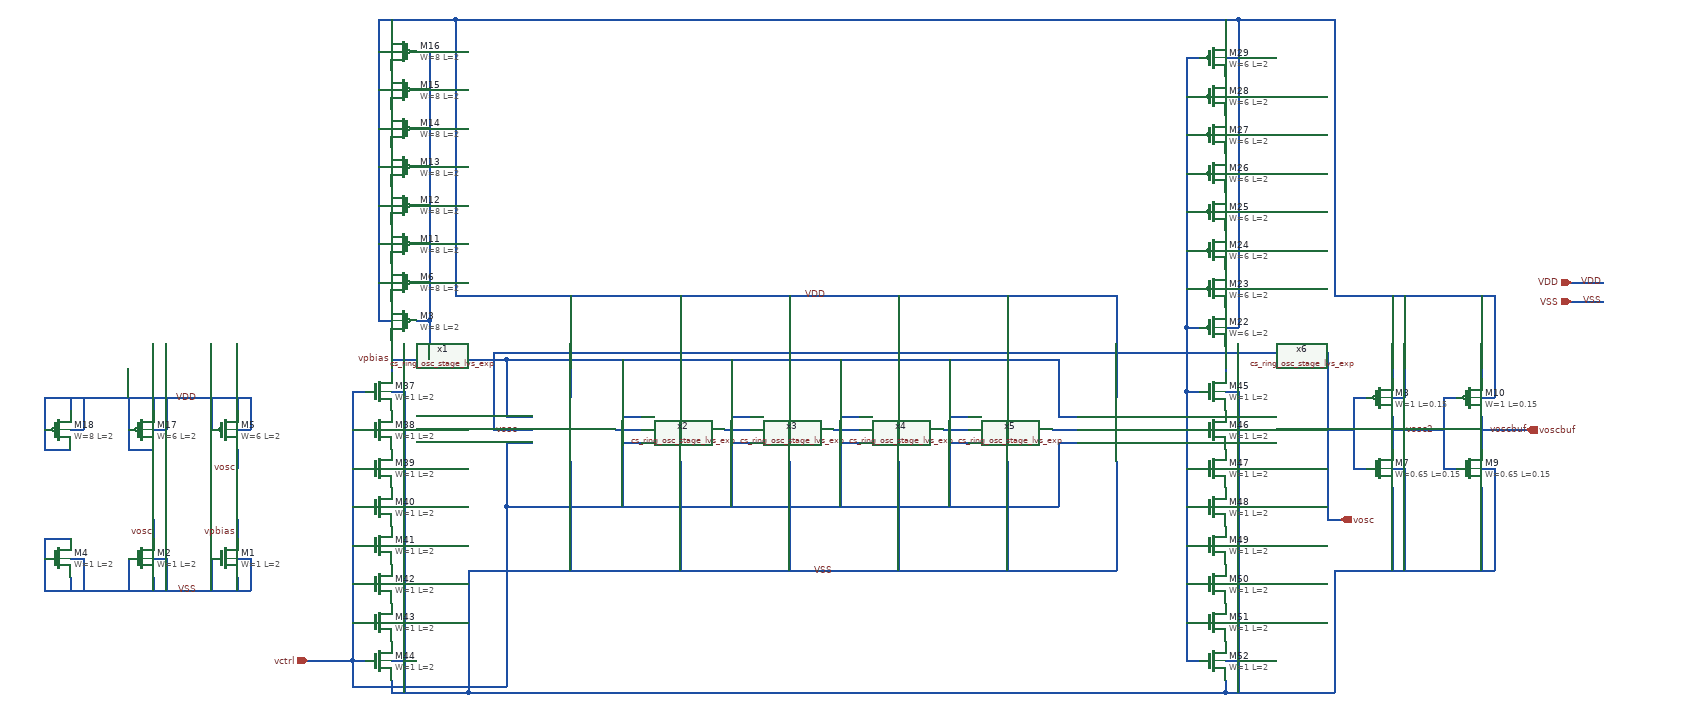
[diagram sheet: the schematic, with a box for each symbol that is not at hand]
v {xschem version=2.9.9 file_version=1.2 

* Copyright 2020 Stefan Frederik Schippers
* 
* Licensed under the Apache License, Version 2.0 (the "License");
* you may not use this file except in compliance with the License.
* You may obtain a copy of the License at
*
*     https://www.apache.org/licenses/LICENSE-2.0
*
* Unless required by applicable law or agreed to in writing, software
* distributed under the License is distributed on an "AS IS" BASIS,
* WITHOUT WARRANTIES OR CONDITIONS OF ANY KIND, either express or implied.
* See the License for the specific language governing permissions and
* limitations under the License.

}
G {}
K {}
V {}
S {}
E {}
N -120 -140 -50 -140 { lab=vctrl}
N 130 -610 190 -610 { lab=vpbias}
N 190 -610 190 -520 { lab=vpbias}
N 190 -520 230 -520 { lab=vpbias}
N 190 -480 190 -380 { lab=vctrl}
N 190 -480 230 -480 { lab=vctrl}
N 360 -500 400 -500 { lab=#net1}
N 530 -500 570 -500 { lab=#net2}
N 700 -500 740 -500 { lab=#net3}
N 870 -500 910 -500 { lab=#net4}
N 1040 -500 1080 -500 { lab=#net5}
N 1210 -500 1250 -500 { lab=#net6}
N 190 -610 1050 -610 { lab=vpbias}
N 1050 -520 1080 -520 { lab=vpbias}
N 190 -380 1050 -380 { lab=vctrl}
N 1050 -480 1080 -480 { lab=vctrl}
N 880 -520 910 -520 { lab=vpbias}
N 880 -480 910 -480 { lab=vctrl}
N 710 -520 740 -520 { lab=vpbias}
N 710 -480 740 -480 { lab=vctrl}
N 540 -480 570 -480 { lab=vctrl}
N 540 -520 570 -520 { lab=vpbias}
N 370 -520 400 -520 { lab=vpbias}
N 370 -610 370 -520 { lab=vpbias}
N 370 -480 400 -480 { lab=vctrl}
N 370 -480 370 -380 { lab=vctrl}
N 170 -500 230 -500 { lab=vosc}
N 1470 -500 1470 -360 { lab=vosc}
N 1570 -550 1590 -550 { lab=VDD}
N 1570 -520 1570 -470 { lab=vosc2}
N 1570 -440 1590 -440 { lab=VSS}
N 1510 -550 1510 -490 { lab=vosc}
N 1510 -550 1530 -550 { lab=vosc}
N 1510 -490 1510 -440 { lab=vosc}
N 1510 -440 1530 -440 { lab=vosc}
N 1570 -710 1570 -580 { lab=VDD}
N 1590 -710 1590 -550 { lab=VDD}
N 1570 -410 1570 -280 { lab=VSS}
N 1590 -440 1590 -280 { lab=VSS}
N 1710 -550 1730 -550 { lab=VDD}
N 1710 -520 1710 -470 { lab=voscbuf}
N 1710 -440 1730 -440 { lab=VSS}
N 1650 -550 1650 -490 { lab=vosc2}
N 1650 -550 1670 -550 { lab=vosc2}
N 1650 -490 1650 -440 { lab=vosc2}
N 1650 -440 1670 -440 { lab=vosc2}
N 1710 -710 1710 -580 { lab=VDD}
N 1730 -710 1730 -550 { lab=VDD}
N 1710 -410 1710 -280 { lab=VSS}
N 1730 -440 1730 -280 { lab=VSS}
N 1570 -500 1650 -500 { lab=vosc2}
N 1470 -500 1510 -500 { lab=vosc}
N 290 -710 290 -550 { lab=VDD}
N 290 -450 290 -280 { lab=VSS}
N 540 -610 540 -520 { lab=vpbias}
N 540 -480 540 -380 { lab=vctrl}
N 460 -710 460 -550 { lab=VDD}
N 460 -450 460 -280 { lab=VSS}
N 710 -610 710 -520 { lab=vpbias}
N 710 -480 710 -380 { lab=vctrl}
N 630 -710 630 -550 { lab=VDD}
N 630 -450 630 -280 { lab=VSS}
N 880 -610 880 -520 { lab=vpbias}
N 880 -480 880 -380 { lab=vctrl}
N 800 -710 800 -550 { lab=VDD}
N 800 -450 800 -280 { lab=VSS}
N 1050 -610 1050 -520 { lab=vpbias}
N 1050 -480 1050 -380 { lab=vctrl}
N 970 -710 970 -550 { lab=VDD}
N 970 -450 970 -280 { lab=VSS}
N 1140 -710 1140 -550 { lab=VDD}
N 1140 -450 1140 -280 { lab=VSS}
N 1850 -730 1900 -730 { lab=VDD}
N 1850 -700 1900 -700 { lab=VSS}
N 1710 -500 1780 -500 { lab=voscbuf}
N 1470 -360 1490 -360 { lab=vosc}
N -10 -670 10 -670 { lab=VDD}
N 10 -1140 10 -1120 { lab=VDD}
N -10 -730 10 -730 { lab=VDD}
N -10 -790 10 -790 { lab=VDD}
N -10 -850 10 -850 { lab=VDD}
N -10 -910 10 -910 { lab=VDD}
N -10 -970 10 -970 { lab=VDD}
N -10 -1030 10 -1030 { lab=VDD}
N -10 -1090 10 -1090 { lab=VDD}
N 50 -1090 70 -1090 { lab=vpbias}
N 70 -1090 70 -670 { lab=vpbias}
N 50 -670 70 -670 { lab=vpbias}
N 50 -730 70 -730 { lab=vpbias}
N 50 -790 70 -790 { lab=vpbias}
N 50 -850 70 -850 { lab=vpbias}
N 50 -910 70 -910 { lab=vpbias}
N 50 -970 70 -970 { lab=vpbias}
N 50 -1030 70 -1030 { lab=vpbias}
N 10 -110 10 -90 { lab=VSS}
N 10 -560 30 -560 { lab=VSS}
N 10 -500 30 -500 { lab=VSS}
N 10 -440 30 -440 { lab=VSS}
N 10 -380 30 -380 { lab=VSS}
N 10 -320 30 -320 { lab=VSS}
N 10 -260 30 -260 { lab=VSS}
N 10 -200 30 -200 { lab=VSS}
N 10 -140 30 -140 { lab=VSS}
N -50 -560 -30 -560 { lab=vctrl}
N -50 -560 -50 -140 { lab=vctrl}
N -50 -140 -30 -140 { lab=vctrl}
N -50 -200 -30 -200 { lab=vctrl}
N -50 -260 -30 -260 { lab=vctrl}
N -50 -320 -30 -320 { lab=vctrl}
N -50 -380 -30 -380 { lab=vctrl}
N -50 -440 -30 -440 { lab=vctrl}
N -50 -500 -30 -500 { lab=vctrl}
N 30 -560 30 -90 { lab=VSS}
N 10 -640 10 -590 { lab=vpbias}
N 10 -90 130 -90 { lab=VSS}
N 130 -280 130 -90 { lab=VSS}
N 190 -380 190 -100 { lab=vctrl}
N -50 -100 190 -100 { lab=vctrl}
N -50 -140 -50 -100 { lab=vctrl}
N 10 -610 130 -610 { lab=vpbias}
N -10 -1140 -10 -670 { lab=VDD}
N -10 -1140 110 -1140 { lab=VDD}
N 110 -1140 110 -710 { lab=VDD}
N 1310 -660 1330 -660 { lab=VDD}
N 1310 -720 1330 -720 { lab=VDD}
N 1310 -780 1330 -780 { lab=VDD}
N 1310 -840 1330 -840 { lab=VDD}
N 1310 -900 1330 -900 { lab=VDD}
N 1310 -960 1330 -960 { lab=VDD}
N 1310 -1020 1330 -1020 { lab=VDD}
N 1310 -1080 1330 -1080 { lab=VDD}
N 1310 -560 1330 -560 { lab=VSS}
N 1310 -500 1330 -500 { lab=VSS}
N 1310 -440 1330 -440 { lab=VSS}
N 1310 -380 1330 -380 { lab=VSS}
N 1310 -320 1330 -320 { lab=VSS}
N 1310 -260 1330 -260 { lab=VSS}
N 1310 -200 1330 -200 { lab=VSS}
N 1310 -140 1330 -140 { lab=VSS}
N 1310 -630 1310 -590 { lab=vosc}
N 1250 -560 1270 -560 { lab=#net6}
N 1250 -140 1270 -140 { lab=#net6}
N 1250 -200 1270 -200 { lab=#net6}
N 1250 -260 1270 -260 { lab=#net6}
N 1250 -320 1270 -320 { lab=#net6}
N 1250 -380 1270 -380 { lab=#net6}
N 1250 -440 1270 -440 { lab=#net6}
N 1250 -500 1270 -500 { lab=#net6}
N 1250 -1080 1270 -1080 { lab=#net6}
N 1250 -1080 1250 -660 { lab=#net6}
N 1250 -660 1270 -660 { lab=#net6}
N 1250 -720 1270 -720 { lab=#net6}
N 1250 -780 1270 -780 { lab=#net6}
N 1250 -840 1270 -840 { lab=#net6}
N 1250 -900 1270 -900 { lab=#net6}
N 1250 -960 1270 -960 { lab=#net6}
N 1250 -1020 1270 -1020 { lab=#net6}
N 1250 -560 1250 -140 { lab=#net6}
N 130 -90 1310 -90 { lab=VSS}
N 1310 -110 1310 -90 { lab=VSS}
N 1330 -560 1330 -90 { lab=VSS}
N 130 -280 1140 -280 { lab=VSS}
N 110 -710 1140 -710 { lab=VDD}
N 1310 -1130 1310 -1110 { lab=VDD}
N 1250 -660 1250 -560 { lab=#net6}
N 1470 -610 1470 -500 { lab=vosc}
N 110 -1140 1330 -1140 { lab=VDD}
N 1330 -1140 1330 -1120 { lab=VDD}
N 1330 -1120 1330 -660 { lab=VDD}
N 1310 -1140 1310 -1130 { lab=VDD}
N 1330 -1140 1480 -1140 { lab=VDD}
N 1480 -1140 1480 -710 { lab=VDD}
N 1480 -710 1730 -710 { lab=VDD}
N 1310 -90 1480 -90 { lab=VSS}
N 1480 -280 1480 -90 { lab=VSS}
N 1480 -280 1730 -280 { lab=VSS}
N 70 -670 70 -610 { lab=vpbias}
N 1470 -620 1470 -610 { lab=vosc}
N 1310 -620 1470 -620 { lab=vosc}
N 170 -620 1310 -620 { lab=vosc}
N 170 -620 170 -500 { lab=vosc}
N -230 -300 -210 -300 { lab=VSS}
N -210 -300 -210 -250 { lab=VSS}
N -230 -270 -230 -250 { lab=VSS}
N -270 -300 -270 -250 { lab=VSS}
N -230 -360 -230 -330 { lab=vpbias}
N -360 -300 -340 -300 { lab=VSS}
N -340 -300 -340 -250 { lab=VSS}
N -360 -270 -360 -250 { lab=VSS}
N -400 -300 -400 -250 { lab=VSS}
N -360 -360 -360 -330 { lab=vosc}
N -490 -300 -470 -300 { lab=VSS}
N -470 -300 -470 -250 { lab=VSS}
N -490 -270 -490 -250 { lab=VSS}
N -530 -300 -530 -250 { lab=VSS}
N -530 -250 -210 -250 { lab=VSS}
N -230 -470 -230 -440 { lab=vosc}
N -230 -550 -230 -530 { lab=#net7}
N -230 -500 -210 -500 { lab=#net7}
N -210 -550 -210 -500 { lab=#net7}
N -270 -550 -270 -500 { lab=#net7}
N -360 -550 -360 -530 { lab=#net7}
N -360 -500 -340 -500 { lab=#net7}
N -340 -550 -340 -500 { lab=#net7}
N -400 -550 -400 -500 { lab=#net7}
N -400 -470 -360 -470 { lab=#net7}
N -400 -500 -400 -470 { lab=#net7}
N -530 -330 -490 -330 { lab=VSS}
N -530 -330 -530 -300 { lab=VSS}
N -490 -550 -490 -530 { lab=#net7}
N -490 -500 -470 -500 { lab=#net7}
N -470 -550 -470 -500 { lab=#net7}
N -530 -550 -530 -500 { lab=#net7}
N -530 -470 -490 -470 { lab=#net7}
N -530 -500 -530 -470 { lab=#net7}
N -530 -550 -210 -550 { lab=#net7}
C {devices/title.sym} 160 -30 0 0 {name=l1 author="Nikhil Poole"}
C {devices/lab_wire.sym} 210 -500 0 0 {name=l9 sig_type=std_logic lab=vosc}
C {devices/lab_wire.sym} 10 -610 0 0 {name=l10 sig_type=std_logic lab=vpbias}
C {sky130_fd_pr/nfet_01v8.sym} 1550 -440 0 0 {name=M7
L=0.15
W=0.65
nf=1
mult=1
ad="'int((nf+1)/2) * W/nf * 0.29'" 
pd="'2*int((nf+1)/2) * (W/nf + 0.29)'"
as="'int((nf+2)/2) * W/nf * 0.29'" 
ps="'2*int((nf+2)/2) * (W/nf + 0.29)'"
nrd="'0.29 / W'" nrs="'0.29 / W'"
sa=0 sb=0 sd=0
model=nfet_01v8
spiceprefix=X
}
C {sky130_fd_pr/pfet_01v8_hvt.sym} 1550 -550 0 0 {name=M8
L=0.15
W=1
nf=1
mult=1
ad="'int((nf+1)/2) * W/nf * 0.29'" 
pd="'2*int((nf+1)/2) * (W/nf + 0.29)'"
as="'int((nf+2)/2) * W/nf * 0.29'" 
ps="'2*int((nf+2)/2) * (W/nf + 0.29)'"
nrd="'0.29 / W'" nrs="'0.29 / W'"
sa=0 sb=0 sd=0
model=pfet_01v8_hvt
spiceprefix=X
}
C {sky130_fd_pr/nfet_01v8.sym} 1690 -440 0 0 {name=M9
L=0.15
W=0.65
nf=1
mult=4
ad="'int((nf+1)/2) * W/nf * 0.29'" 
pd="'2*int((nf+1)/2) * (W/nf + 0.29)'"
as="'int((nf+2)/2) * W/nf * 0.29'" 
ps="'2*int((nf+2)/2) * (W/nf + 0.29)'"
nrd="'0.29 / W'" nrs="'0.29 / W'"
sa=0 sb=0 sd=0
model=nfet_01v8
spiceprefix=X
}
C {sky130_fd_pr/pfet_01v8_hvt.sym} 1690 -550 0 0 {name=M10
L=0.15
W=1
nf=1
mult=4
ad="'int((nf+1)/2) * W/nf * 0.29'" 
pd="'2*int((nf+1)/2) * (W/nf + 0.29)'"
as="'int((nf+2)/2) * W/nf * 0.29'" 
ps="'2*int((nf+2)/2) * (W/nf + 0.29)'"
nrd="'0.29 / W'" nrs="'0.29 / W'"
sa=0 sb=0 sd=0
model=pfet_01v8_hvt
spiceprefix=X
}
C {devices/lab_wire.sym} 1720 -500 0 1 {name=l11 sig_type=std_logic lab=voscbuf}
C {devices/lab_wire.sym} 1590 -500 0 1 {name=l14 sig_type=std_logic lab=vosc2}
C {devices/lab_wire.sym} 700 -280 0 0 {name=l2 sig_type=std_logic lab=VSS}
C {devices/lab_wire.sym} 690 -710 0 0 {name=l3 sig_type=std_logic lab=VDD}
C {devices/ipin.sym} 1850 -730 0 0 {name=p1 lab=VDD}
C {devices/ipin.sym} 1850 -700 0 0 {name=p2 lab=VSS}
C {devices/lab_wire.sym} 1900 -700 0 0 {name=l4 sig_type=std_logic lab=VSS}
C {devices/lab_wire.sym} 1900 -730 0 0 {name=l5 sig_type=std_logic lab=VDD}
C {devices/ipin.sym} -120 -140 0 0 {name=p3 lab=vctrl}
C {devices/opin.sym} 1780 -500 0 0 {name=p4 lab=voscbuf}
C {devices/opin.sym} 1490 -360 0 0 {name=p5 lab=vosc}
C {/home/users/nhpoole/ee272b/ee272b_mixed_signal_mmwave_accelerator/designs/cs_ring_osc_stage_lvs_exp.sym} 280 -500 0 0 {name=x1}
C {/home/users/nhpoole/ee272b/ee272b_mixed_signal_mmwave_accelerator/designs/cs_ring_osc_stage_lvs_exp.sym} 450 -500 0 0 {name=x2}
C {/home/users/nhpoole/ee272b/ee272b_mixed_signal_mmwave_accelerator/designs/cs_ring_osc_stage_lvs_exp.sym} 620 -500 0 0 {name=x3}
C {/home/users/nhpoole/ee272b/ee272b_mixed_signal_mmwave_accelerator/designs/cs_ring_osc_stage_lvs_exp.sym} 790 -500 0 0 {name=x4}
C {/home/users/nhpoole/ee272b/ee272b_mixed_signal_mmwave_accelerator/designs/cs_ring_osc_stage_lvs_exp.sym} 960 -500 0 0 {name=x5}
C {/home/users/nhpoole/ee272b/ee272b_mixed_signal_mmwave_accelerator/designs/cs_ring_osc_stage_lvs_exp.sym} 1130 -500 0 0 {name=x6}
C {sky130_fd_pr/pfet_01v8_hvt.sym} 30 -670 0 1 {name=M3
L=2
W=8
nf=1
mult=2
ad="'int((nf+1)/2) * W/nf * 0.29'" 
pd="'2*int((nf+1)/2) * (W/nf + 0.29)'"
as="'int((nf+2)/2) * W/nf * 0.29'" 
ps="'2*int((nf+2)/2) * (W/nf + 0.29)'"
nrd="'0.29 / W'" nrs="'0.29 / W'"
sa=0 sb=0 sd=0
model=pfet_01v8_hvt
spiceprefix=X
}
C {sky130_fd_pr/pfet_01v8_hvt.sym} 30 -730 0 1 {name=M6
L=2
W=8
nf=1
mult=2
ad="'int((nf+1)/2) * W/nf * 0.29'" 
pd="'2*int((nf+1)/2) * (W/nf + 0.29)'"
as="'int((nf+2)/2) * W/nf * 0.29'" 
ps="'2*int((nf+2)/2) * (W/nf + 0.29)'"
nrd="'0.29 / W'" nrs="'0.29 / W'"
sa=0 sb=0 sd=0
model=pfet_01v8_hvt
spiceprefix=X
}
C {sky130_fd_pr/pfet_01v8_hvt.sym} 30 -790 0 1 {name=M11
L=2
W=8
nf=1
mult=2
ad="'int((nf+1)/2) * W/nf * 0.29'" 
pd="'2*int((nf+1)/2) * (W/nf + 0.29)'"
as="'int((nf+2)/2) * W/nf * 0.29'" 
ps="'2*int((nf+2)/2) * (W/nf + 0.29)'"
nrd="'0.29 / W'" nrs="'0.29 / W'"
sa=0 sb=0 sd=0
model=pfet_01v8_hvt
spiceprefix=X
}
C {sky130_fd_pr/pfet_01v8_hvt.sym} 30 -850 0 1 {name=M12
L=2
W=8
nf=1
mult=2
ad="'int((nf+1)/2) * W/nf * 0.29'" 
pd="'2*int((nf+1)/2) * (W/nf + 0.29)'"
as="'int((nf+2)/2) * W/nf * 0.29'" 
ps="'2*int((nf+2)/2) * (W/nf + 0.29)'"
nrd="'0.29 / W'" nrs="'0.29 / W'"
sa=0 sb=0 sd=0
model=pfet_01v8_hvt
spiceprefix=X
}
C {sky130_fd_pr/pfet_01v8_hvt.sym} 30 -910 0 1 {name=M13
L=2
W=8
nf=1
mult=2
ad="'int((nf+1)/2) * W/nf * 0.29'" 
pd="'2*int((nf+1)/2) * (W/nf + 0.29)'"
as="'int((nf+2)/2) * W/nf * 0.29'" 
ps="'2*int((nf+2)/2) * (W/nf + 0.29)'"
nrd="'0.29 / W'" nrs="'0.29 / W'"
sa=0 sb=0 sd=0
model=pfet_01v8_hvt
spiceprefix=X
}
C {sky130_fd_pr/pfet_01v8_hvt.sym} 30 -970 0 1 {name=M14
L=2
W=8
nf=1
mult=2
ad="'int((nf+1)/2) * W/nf * 0.29'" 
pd="'2*int((nf+1)/2) * (W/nf + 0.29)'"
as="'int((nf+2)/2) * W/nf * 0.29'" 
ps="'2*int((nf+2)/2) * (W/nf + 0.29)'"
nrd="'0.29 / W'" nrs="'0.29 / W'"
sa=0 sb=0 sd=0
model=pfet_01v8_hvt
spiceprefix=X
}
C {sky130_fd_pr/pfet_01v8_hvt.sym} 30 -1030 0 1 {name=M15
L=2
W=8
nf=1
mult=2
ad="'int((nf+1)/2) * W/nf * 0.29'" 
pd="'2*int((nf+1)/2) * (W/nf + 0.29)'"
as="'int((nf+2)/2) * W/nf * 0.29'" 
ps="'2*int((nf+2)/2) * (W/nf + 0.29)'"
nrd="'0.29 / W'" nrs="'0.29 / W'"
sa=0 sb=0 sd=0
model=pfet_01v8_hvt
spiceprefix=X
}
C {sky130_fd_pr/pfet_01v8_hvt.sym} 30 -1090 0 1 {name=M16
L=2
W=8
nf=1
mult=2
ad="'int((nf+1)/2) * W/nf * 0.29'" 
pd="'2*int((nf+1)/2) * (W/nf + 0.29)'"
as="'int((nf+2)/2) * W/nf * 0.29'" 
ps="'2*int((nf+2)/2) * (W/nf + 0.29)'"
nrd="'0.29 / W'" nrs="'0.29 / W'"
sa=0 sb=0 sd=0
model=pfet_01v8_hvt
spiceprefix=X
}
C {sky130_fd_pr/nfet_01v8.sym} -10 -560 0 0 {name=M37
L=2
W=1
nf=1 
mult=1
ad="'int((nf+1)/2) * W/nf * 0.29'" 
pd="'2*int((nf+1)/2) * (W/nf + 0.29)'"
as="'int((nf+2)/2) * W/nf * 0.29'" 
ps="'2*int((nf+2)/2) * (W/nf + 0.29)'"
nrd="'0.29 / W'" nrs="'0.29 / W'"
sa=0 sb=0 sd=0
model=nfet_01v8
spiceprefix=X
}
C {sky130_fd_pr/nfet_01v8.sym} -10 -500 0 0 {name=M38
L=2
W=1
nf=1 
mult=1
ad="'int((nf+1)/2) * W/nf * 0.29'" 
pd="'2*int((nf+1)/2) * (W/nf + 0.29)'"
as="'int((nf+2)/2) * W/nf * 0.29'" 
ps="'2*int((nf+2)/2) * (W/nf + 0.29)'"
nrd="'0.29 / W'" nrs="'0.29 / W'"
sa=0 sb=0 sd=0
model=nfet_01v8
spiceprefix=X
}
C {sky130_fd_pr/nfet_01v8.sym} -10 -440 0 0 {name=M39
L=2
W=1
nf=1 
mult=1
ad="'int((nf+1)/2) * W/nf * 0.29'" 
pd="'2*int((nf+1)/2) * (W/nf + 0.29)'"
as="'int((nf+2)/2) * W/nf * 0.29'" 
ps="'2*int((nf+2)/2) * (W/nf + 0.29)'"
nrd="'0.29 / W'" nrs="'0.29 / W'"
sa=0 sb=0 sd=0
model=nfet_01v8
spiceprefix=X
}
C {sky130_fd_pr/nfet_01v8.sym} -10 -380 0 0 {name=M40
L=2
W=1
nf=1 
mult=1
ad="'int((nf+1)/2) * W/nf * 0.29'" 
pd="'2*int((nf+1)/2) * (W/nf + 0.29)'"
as="'int((nf+2)/2) * W/nf * 0.29'" 
ps="'2*int((nf+2)/2) * (W/nf + 0.29)'"
nrd="'0.29 / W'" nrs="'0.29 / W'"
sa=0 sb=0 sd=0
model=nfet_01v8
spiceprefix=X
}
C {sky130_fd_pr/nfet_01v8.sym} -10 -320 0 0 {name=M41
L=2
W=1
nf=1 
mult=1
ad="'int((nf+1)/2) * W/nf * 0.29'" 
pd="'2*int((nf+1)/2) * (W/nf + 0.29)'"
as="'int((nf+2)/2) * W/nf * 0.29'" 
ps="'2*int((nf+2)/2) * (W/nf + 0.29)'"
nrd="'0.29 / W'" nrs="'0.29 / W'"
sa=0 sb=0 sd=0
model=nfet_01v8
spiceprefix=X
}
C {sky130_fd_pr/nfet_01v8.sym} -10 -260 0 0 {name=M42
L=2
W=1
nf=1 
mult=1
ad="'int((nf+1)/2) * W/nf * 0.29'" 
pd="'2*int((nf+1)/2) * (W/nf + 0.29)'"
as="'int((nf+2)/2) * W/nf * 0.29'" 
ps="'2*int((nf+2)/2) * (W/nf + 0.29)'"
nrd="'0.29 / W'" nrs="'0.29 / W'"
sa=0 sb=0 sd=0
model=nfet_01v8
spiceprefix=X
}
C {sky130_fd_pr/nfet_01v8.sym} -10 -200 0 0 {name=M43
L=2
W=1
nf=1 
mult=1
ad="'int((nf+1)/2) * W/nf * 0.29'" 
pd="'2*int((nf+1)/2) * (W/nf + 0.29)'"
as="'int((nf+2)/2) * W/nf * 0.29'" 
ps="'2*int((nf+2)/2) * (W/nf + 0.29)'"
nrd="'0.29 / W'" nrs="'0.29 / W'"
sa=0 sb=0 sd=0
model=nfet_01v8
spiceprefix=X
}
C {sky130_fd_pr/nfet_01v8.sym} -10 -140 0 0 {name=M44
L=2
W=1
nf=1 
mult=1
ad="'int((nf+1)/2) * W/nf * 0.29'" 
pd="'2*int((nf+1)/2) * (W/nf + 0.29)'"
as="'int((nf+2)/2) * W/nf * 0.29'" 
ps="'2*int((nf+2)/2) * (W/nf + 0.29)'"
nrd="'0.29 / W'" nrs="'0.29 / W'"
sa=0 sb=0 sd=0
model=nfet_01v8
spiceprefix=X
}
C {sky130_fd_pr/pfet_01v8_hvt.sym} 1290 -660 0 0 {name=M22
L=2
W=6
nf=1
mult=1
ad="'int((nf+1)/2) * W/nf * 0.29'" 
pd="'2*int((nf+1)/2) * (W/nf + 0.29)'"
as="'int((nf+2)/2) * W/nf * 0.29'" 
ps="'2*int((nf+2)/2) * (W/nf + 0.29)'"
nrd="'0.29 / W'" nrs="'0.29 / W'"
sa=0 sb=0 sd=0
model=pfet_01v8_hvt
spiceprefix=X
}
C {sky130_fd_pr/pfet_01v8_hvt.sym} 1290 -720 0 0 {name=M23
L=2
W=6
nf=1
mult=1
ad="'int((nf+1)/2) * W/nf * 0.29'" 
pd="'2*int((nf+1)/2) * (W/nf + 0.29)'"
as="'int((nf+2)/2) * W/nf * 0.29'" 
ps="'2*int((nf+2)/2) * (W/nf + 0.29)'"
nrd="'0.29 / W'" nrs="'0.29 / W'"
sa=0 sb=0 sd=0
model=pfet_01v8_hvt
spiceprefix=X
}
C {sky130_fd_pr/pfet_01v8_hvt.sym} 1290 -780 0 0 {name=M24
L=2
W=6
nf=1
mult=1
ad="'int((nf+1)/2) * W/nf * 0.29'" 
pd="'2*int((nf+1)/2) * (W/nf + 0.29)'"
as="'int((nf+2)/2) * W/nf * 0.29'" 
ps="'2*int((nf+2)/2) * (W/nf + 0.29)'"
nrd="'0.29 / W'" nrs="'0.29 / W'"
sa=0 sb=0 sd=0
model=pfet_01v8_hvt
spiceprefix=X
}
C {sky130_fd_pr/pfet_01v8_hvt.sym} 1290 -840 0 0 {name=M25
L=2
W=6
nf=1
mult=1
ad="'int((nf+1)/2) * W/nf * 0.29'" 
pd="'2*int((nf+1)/2) * (W/nf + 0.29)'"
as="'int((nf+2)/2) * W/nf * 0.29'" 
ps="'2*int((nf+2)/2) * (W/nf + 0.29)'"
nrd="'0.29 / W'" nrs="'0.29 / W'"
sa=0 sb=0 sd=0
model=pfet_01v8_hvt
spiceprefix=X
}
C {sky130_fd_pr/pfet_01v8_hvt.sym} 1290 -900 0 0 {name=M26
L=2
W=6
nf=1
mult=1
ad="'int((nf+1)/2) * W/nf * 0.29'" 
pd="'2*int((nf+1)/2) * (W/nf + 0.29)'"
as="'int((nf+2)/2) * W/nf * 0.29'" 
ps="'2*int((nf+2)/2) * (W/nf + 0.29)'"
nrd="'0.29 / W'" nrs="'0.29 / W'"
sa=0 sb=0 sd=0
model=pfet_01v8_hvt
spiceprefix=X
}
C {sky130_fd_pr/pfet_01v8_hvt.sym} 1290 -960 0 0 {name=M27
L=2
W=6
nf=1
mult=1
ad="'int((nf+1)/2) * W/nf * 0.29'" 
pd="'2*int((nf+1)/2) * (W/nf + 0.29)'"
as="'int((nf+2)/2) * W/nf * 0.29'" 
ps="'2*int((nf+2)/2) * (W/nf + 0.29)'"
nrd="'0.29 / W'" nrs="'0.29 / W'"
sa=0 sb=0 sd=0
model=pfet_01v8_hvt
spiceprefix=X
}
C {sky130_fd_pr/pfet_01v8_hvt.sym} 1290 -1020 0 0 {name=M28
L=2
W=6
nf=1
mult=1
ad="'int((nf+1)/2) * W/nf * 0.29'" 
pd="'2*int((nf+1)/2) * (W/nf + 0.29)'"
as="'int((nf+2)/2) * W/nf * 0.29'" 
ps="'2*int((nf+2)/2) * (W/nf + 0.29)'"
nrd="'0.29 / W'" nrs="'0.29 / W'"
sa=0 sb=0 sd=0
model=pfet_01v8_hvt
spiceprefix=X
}
C {sky130_fd_pr/pfet_01v8_hvt.sym} 1290 -1080 0 0 {name=M29
L=2
W=6
nf=1
mult=1
ad="'int((nf+1)/2) * W/nf * 0.29'" 
pd="'2*int((nf+1)/2) * (W/nf + 0.29)'"
as="'int((nf+2)/2) * W/nf * 0.29'" 
ps="'2*int((nf+2)/2) * (W/nf + 0.29)'"
nrd="'0.29 / W'" nrs="'0.29 / W'"
sa=0 sb=0 sd=0
model=pfet_01v8_hvt
spiceprefix=X
}
C {sky130_fd_pr/nfet_01v8.sym} 1290 -560 0 0 {name=M45
L=2
W=1
nf=1 
mult=1
ad="'int((nf+1)/2) * W/nf * 0.29'" 
pd="'2*int((nf+1)/2) * (W/nf + 0.29)'"
as="'int((nf+2)/2) * W/nf * 0.29'" 
ps="'2*int((nf+2)/2) * (W/nf + 0.29)'"
nrd="'0.29 / W'" nrs="'0.29 / W'"
sa=0 sb=0 sd=0
model=nfet_01v8
spiceprefix=X
}
C {sky130_fd_pr/nfet_01v8.sym} 1290 -500 0 0 {name=M46
L=2
W=1
nf=1 
mult=1
ad="'int((nf+1)/2) * W/nf * 0.29'" 
pd="'2*int((nf+1)/2) * (W/nf + 0.29)'"
as="'int((nf+2)/2) * W/nf * 0.29'" 
ps="'2*int((nf+2)/2) * (W/nf + 0.29)'"
nrd="'0.29 / W'" nrs="'0.29 / W'"
sa=0 sb=0 sd=0
model=nfet_01v8
spiceprefix=X
}
C {sky130_fd_pr/nfet_01v8.sym} 1290 -440 0 0 {name=M47
L=2
W=1
nf=1 
mult=1
ad="'int((nf+1)/2) * W/nf * 0.29'" 
pd="'2*int((nf+1)/2) * (W/nf + 0.29)'"
as="'int((nf+2)/2) * W/nf * 0.29'" 
ps="'2*int((nf+2)/2) * (W/nf + 0.29)'"
nrd="'0.29 / W'" nrs="'0.29 / W'"
sa=0 sb=0 sd=0
model=nfet_01v8
spiceprefix=X
}
C {sky130_fd_pr/nfet_01v8.sym} 1290 -380 0 0 {name=M48
L=2
W=1
nf=1 
mult=1
ad="'int((nf+1)/2) * W/nf * 0.29'" 
pd="'2*int((nf+1)/2) * (W/nf + 0.29)'"
as="'int((nf+2)/2) * W/nf * 0.29'" 
ps="'2*int((nf+2)/2) * (W/nf + 0.29)'"
nrd="'0.29 / W'" nrs="'0.29 / W'"
sa=0 sb=0 sd=0
model=nfet_01v8
spiceprefix=X
}
C {sky130_fd_pr/nfet_01v8.sym} 1290 -320 0 0 {name=M49
L=2
W=1
nf=1 
mult=1
ad="'int((nf+1)/2) * W/nf * 0.29'" 
pd="'2*int((nf+1)/2) * (W/nf + 0.29)'"
as="'int((nf+2)/2) * W/nf * 0.29'" 
ps="'2*int((nf+2)/2) * (W/nf + 0.29)'"
nrd="'0.29 / W'" nrs="'0.29 / W'"
sa=0 sb=0 sd=0
model=nfet_01v8
spiceprefix=X
}
C {sky130_fd_pr/nfet_01v8.sym} 1290 -260 0 0 {name=M50
L=2
W=1
nf=1 
mult=1
ad="'int((nf+1)/2) * W/nf * 0.29'" 
pd="'2*int((nf+1)/2) * (W/nf + 0.29)'"
as="'int((nf+2)/2) * W/nf * 0.29'" 
ps="'2*int((nf+2)/2) * (W/nf + 0.29)'"
nrd="'0.29 / W'" nrs="'0.29 / W'"
sa=0 sb=0 sd=0
model=nfet_01v8
spiceprefix=X
}
C {sky130_fd_pr/nfet_01v8.sym} 1290 -200 0 0 {name=M51
L=2
W=1
nf=1 
mult=1
ad="'int((nf+1)/2) * W/nf * 0.29'" 
pd="'2*int((nf+1)/2) * (W/nf + 0.29)'"
as="'int((nf+2)/2) * W/nf * 0.29'" 
ps="'2*int((nf+2)/2) * (W/nf + 0.29)'"
nrd="'0.29 / W'" nrs="'0.29 / W'"
sa=0 sb=0 sd=0
model=nfet_01v8
spiceprefix=X
}
C {sky130_fd_pr/nfet_01v8.sym} 1290 -140 0 0 {name=M52
L=2
W=1
nf=1 
mult=1
ad="'int((nf+1)/2) * W/nf * 0.29'" 
pd="'2*int((nf+1)/2) * (W/nf + 0.29)'"
as="'int((nf+2)/2) * W/nf * 0.29'" 
ps="'2*int((nf+2)/2) * (W/nf + 0.29)'"
nrd="'0.29 / W'" nrs="'0.29 / W'"
sa=0 sb=0 sd=0
model=nfet_01v8
spiceprefix=X
}
C {sky130_fd_pr/nfet_01v8.sym} -250 -300 0 0 {name=M1
L=2
W=1
nf=1 
mult=1
ad="'int((nf+1)/2) * W/nf * 0.29'" 
pd="'2*int((nf+1)/2) * (W/nf + 0.29)'"
as="'int((nf+2)/2) * W/nf * 0.29'" 
ps="'2*int((nf+2)/2) * (W/nf + 0.29)'"
nrd="'0.29 / W'" nrs="'0.29 / W'"
sa=0 sb=0 sd=0
model=nfet_01v8
spiceprefix=X
}
C {devices/lab_wire.sym} -230 -340 0 0 {name=l6 sig_type=std_logic lab=vpbias}
C {sky130_fd_pr/nfet_01v8.sym} -380 -300 0 0 {name=M2
L=2
W=1
nf=1 
mult=1
ad="'int((nf+1)/2) * W/nf * 0.29'" 
pd="'2*int((nf+1)/2) * (W/nf + 0.29)'"
as="'int((nf+2)/2) * W/nf * 0.29'" 
ps="'2*int((nf+2)/2) * (W/nf + 0.29)'"
nrd="'0.29 / W'" nrs="'0.29 / W'"
sa=0 sb=0 sd=0
model=nfet_01v8
spiceprefix=X
}
C {devices/lab_wire.sym} -360 -340 0 0 {name=l7 sig_type=std_logic lab=vosc}
C {sky130_fd_pr/nfet_01v8.sym} -510 -300 0 0 {name=M4
L=2
W=1
nf=1 
mult=2
ad="'int((nf+1)/2) * W/nf * 0.29'" 
pd="'2*int((nf+1)/2) * (W/nf + 0.29)'"
as="'int((nf+2)/2) * W/nf * 0.29'" 
ps="'2*int((nf+2)/2) * (W/nf + 0.29)'"
nrd="'0.29 / W'" nrs="'0.29 / W'"
sa=0 sb=0 sd=0
model=nfet_01v8
spiceprefix=X
}
C {devices/lab_wire.sym} -290 -250 0 0 {name=l12 sig_type=std_logic lab=VSS}
C {sky130_fd_pr/pfet_01v8_hvt.sym} -250 -500 0 0 {name=M5
L=2
W=6
nf=1
mult=1
ad="'int((nf+1)/2) * W/nf * 0.29'" 
pd="'2*int((nf+1)/2) * (W/nf + 0.29)'"
as="'int((nf+2)/2) * W/nf * 0.29'" 
ps="'2*int((nf+2)/2) * (W/nf + 0.29)'"
nrd="'0.29 / W'" nrs="'0.29 / W'"
sa=0 sb=0 sd=0
model=pfet_01v8_hvt
spiceprefix=X
}
C {devices/lab_wire.sym} -230 -440 0 0 {name=l13 sig_type=std_logic lab=vosc}
C {sky130_fd_pr/pfet_01v8_hvt.sym} -380 -500 0 0 {name=M17
L=2
W=6
nf=1
mult=1
ad="'int((nf+1)/2) * W/nf * 0.29'" 
pd="'2*int((nf+1)/2) * (W/nf + 0.29)'"
as="'int((nf+2)/2) * W/nf * 0.29'" 
ps="'2*int((nf+2)/2) * (W/nf + 0.29)'"
nrd="'0.29 / W'" nrs="'0.29 / W'"
sa=0 sb=0 sd=0
model=pfet_01v8_hvt
spiceprefix=X
}
C {sky130_fd_pr/pfet_01v8_hvt.sym} -510 -500 0 0 {name=M18
L=2
W=8
nf=1
mult=2
ad="'int((nf+1)/2) * W/nf * 0.29'" 
pd="'2*int((nf+1)/2) * (W/nf + 0.29)'"
as="'int((nf+2)/2) * W/nf * 0.29'" 
ps="'2*int((nf+2)/2) * (W/nf + 0.29)'"
nrd="'0.29 / W'" nrs="'0.29 / W'"
sa=0 sb=0 sd=0
model=pfet_01v8_hvt
spiceprefix=X
}
C {devices/lab_wire.sym} -290 -550 0 0 {name=l8 sig_type=std_logic lab=VDD}
